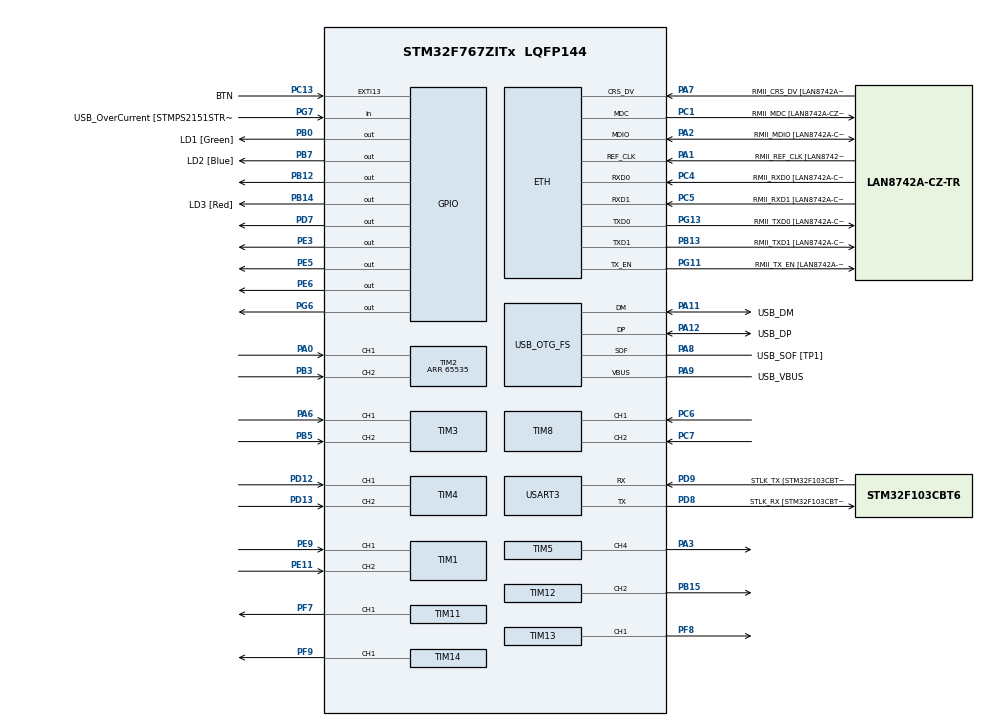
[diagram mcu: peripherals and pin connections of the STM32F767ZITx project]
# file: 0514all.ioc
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ETH.MediaInterface=HAL_ETH_RMII_MODE
ETH.PHY_Name=LAN8742A_PHY_ADDRESS
ETH.PHY_Value=0
ETH.PhyAddress=0
Mcu.Family=STM32F7
Mcu.Name=STM32F767ZITx
Mcu.Package=LQFP144
NVIC.EXTI15_10_IRQn=true\:0\:0\:false\:false\:true\:true\:true\:true
NVIC.PriorityGroup=NVIC_PRIORITYGROUP_4
NVIC.TIM1_BRK_TIM9_IRQn=true\:0\:0\:false\:false\:true\:true\:true\:true
PA0/WKUP.Signal=S_TIM2_CH1_ETR
PA1.GPIO_Label=RMII_REF_CLK [LAN8742A-CZ-TR_REFCLK0]
PA1.Mode=RMII
PA1.Signal=ETH_REF_CLK
PA10.GPIO_Label=USB_ID
PA10.Signal=USB_OTG_FS_ID
PA11.GPIO_Label=USB_DM
PA11.Mode=Device_Only
PA11.Signal=USB_OTG_FS_DM
PA12.GPIO_Label=USB_DP
PA12.Mode=Device_Only
PA12.Signal=USB_OTG_FS_DP
PA13.GPIO_Label=TMS
PA13.Mode=Serial_Wire
PA13.Signal=SYS_JTMS-SWDIO
PA14.GPIO_Label=TCK
PA14.Mode=Serial_Wire
PA14.Signal=SYS_JTCK-SWCLK
PA2.GPIO_Label=RMII_MDIO [LAN8742A-CZ-TR_MDIO]
PA2.Mode=RMII
PA2.Signal=ETH_MDIO
PA3.Signal=S_TIM5_CH4
PA6.Signal=S_TIM3_CH1
PA7.GPIO_Label=RMII_CRS_DV [LAN8742A-CZ-TR_CRS_DV]
PA7.Mode=RMII
PA7.Signal=ETH_CRS_DV
PA8.GPIO_Label=USB_SOF [TP1]
PA8.Mode=Activate_SOF_FS
PA8.Signal=USB_OTG_FS_SOF
PA9.GPIO_Label=USB_VBUS
PA9.Mode=Activate_VBUS
PA9.Signal=USB_OTG_FS_VBUS
PB0.GPIO_Label=LD1 [Green]
PB0.Signal=GPIO_Output
PB12.Signal=GPIO_Output
PB13.GPIO_Label=RMII_TXD1 [LAN8742A-CZ-TR_TXD1]
PB13.Mode=RMII
PB13.Signal=ETH_TXD1
PB14.GPIO_Label=LD3 [Red]
PB14.Signal=GPIO_Output
PB15.Signal=S_TIM12_CH2
PB3.Signal=S_TIM2_CH2
PB5.Signal=S_TIM3_CH2
PB7.GPIO_Label=LD2 [Blue]
PB7.Signal=GPIO_Output
PC1.GPIO_Label=RMII_MDC [LAN8742A-CZ-TR_MDC]
PC1.Mode=RMII
PC1.Signal=ETH_MDC
PC13.GPIO_Label=BTN
PC13.Signal=GPXTI13
PC14/OSC32_IN.Mode=LSE-External-Oscillator
PC14/OSC32_IN.Signal=RCC_OSC32_IN
PC15/OSC32_OUT.Mode=LSE-External-Oscillator
PC15/OSC32_OUT.Signal=RCC_OSC32_OUT
PC4.GPIO_Label=RMII_RXD0 [LAN8742A-CZ-TR_RXD0]
PC4.Mode=RMII
PC4.Signal=ETH_RXD0
PC5.GPIO_Label=RMII_RXD1 [LAN8742A-CZ-TR_RXD1]
PC5.Mode=RMII
PC5.Signal=ETH_RXD1
PC6.Signal=S_TIM8_CH1
PC7.Signal=S_TIM8_CH2
PD12.Signal=S_TIM4_CH1
PD13.Signal=S_TIM4_CH2
PD7.Signal=GPIO_Output
PD8.GPIO_Label=STLK_RX [STM32F103CBT6_PA3]
PD8.Mode=Asynchronous
PD8.Signal=USART3_TX
PD9.GPIO_Label=STLK_TX [STM32F103CBT6_PA2]
PD9.Mode=Asynchronous
PD9.Signal=USART3_RX
PE11.Signal=S_TIM1_CH2
PE3.Signal=GPIO_Output
PE5.Signal=GPIO_Output
PE6.Signal=GPIO_Output
PE9.Signal=S_TIM1_CH1
PF7.Signal=S_TIM11_CH1
PF8.Signal=S_TIM13_CH1
PF9.Signal=S_TIM14_CH1
PG11.GPIO_Label=RMII_TX_EN [LAN8742A-CZ-TR_TXEN]
PG11.Mode=RMII
PG11.Signal=ETH_TX_EN
PG13.GPIO_Label=RMII_TXD0 [LAN8742A-CZ-TR_TXD0]
PG13.Mode=RMII
PG13.Signal=ETH_TXD0
PG6.Signal=GPIO_Output
PG7.GPIO_Label=USB_OverCurrent [STMPS2151STR_FAULT]
PG7.Signal=GPIO_Input
PH0/OSC_IN.GPIO_Label=MCO [STM32F103CBT6_PA8]
PH0/OSC_IN.Mode=HSE-External-Clock-Source
PH0/OSC_IN.Signal=RCC_OSC_IN
PH1/OSC_OUT.Mode=HSE-External-Clock-Source
PH1/OSC_OUT.Signal=RCC_OSC_OUT
ProjectManager.HeapSize=0x200
ProjectManager.StackSize=0x400
ProjectManager.TargetToolchain=STM32CubeIDE
RCC.48MHZClocksFreq_Value=24000000
RCC.AHBFreq_Value=96000000
RCC.APB1CLKDivider=RCC_HCLK_DIV2
RCC.APB1Freq_Value=48000000
RCC.APB1TimFreq_Value=96000000
RCC.APB2Freq_Value=96000000
RCC.APB2TimFreq_Value=96000000
RCC.CortexFreq_Value=96000000
RCC.HCLKFreq_Value=96000000
RCC.HSE_VALUE=8000000
RCC.HSI_VALUE=16000000
RCC.PLLM=4
RCC.PLLMUL=RCC_PLL_MUL9
RCC.PLLN=96
RCC.PLLQ=4
RCC.PRESCALERUSB=RCC_USBCLKSOURCE_PLL_DIV1_5
RCC.SYSCLKFreq_VALUE=96000000
RCC.SYSCLKSource=RCC_SYSCLKSOURCE_PLLCLK
RCC.SYSCLKSourceVirtual=RCC_SYSCLKSOURCE_PLLCLK
RCC.USBFreq_Value=48000000
RCC.VCOOutputFreq_Value=192000000
SH.S_TIM11_CH1.0=TIM11_CH1,PWM Generation1 CH1
SH.S_TIM12_CH2.0=TIM12_CH2,PWM Generation2 CH2
SH.S_TIM13_CH1.0=TIM13_CH1,PWM Generation1 CH1
SH.S_TIM14_CH1.0=TIM14_CH1,PWM Generation1 CH1
SH.S_TIM1_CH1.0=TIM1_CH1,Encoder_Interface
SH.S_TIM1_CH2.0=TIM1_CH2,Encoder_Interface
SH.S_TIM2_CH1_ETR.0=TIM2_CH1,Encoder_Interface
SH.S_TIM2_CH2.0=TIM2_CH2,Encoder_Interface
SH.S_TIM3_CH1.0=TIM3_CH1,Encoder_Interface
SH.S_TIM3_CH2.0=TIM3_CH2,Encoder_Interface
SH.S_TIM4_CH1.0=TIM4_CH1,Encoder_Interface
SH.S_TIM4_CH2.0=TIM4_CH2,Encoder_Interface
SH.S_TIM5_CH4.0=TIM5_CH4,PWM Generation4 CH4
SH.S_TIM8_CH1.0=TIM8_CH1,Encoder_Interface
SH.S_TIM8_CH2.0=TIM8_CH2,Encoder_Interface
TIM1.EncoderMode=TIM_ENCODERMODE_TI12
TIM11.Channel=TIM_CHANNEL_1
TIM11.Period=4200-1
TIM12.Channel-PWM\ Generation2\ CH2=TIM_CHANNEL_2
TIM12.Period=4200-1
TIM13.Channel=TIM_CHANNEL_1
TIM13.Period=4200-1
TIM14.Channel=TIM_CHANNEL_1
TIM14.Period=4200-1
TIM2.EncoderMode=TIM_ENCODERMODE_TI12
TIM2.Period=65535
TIM4.EncoderMode=TIM_ENCODERMODE_TI12
TIM5.Channel-PWM\ Generation4\ CH4=TIM_CHANNEL_4
TIM5.Period=4200-1
TIM8.EncoderMode=TIM_ENCODERMODE_TI12
TIM9.Period=840-1
TIM9.Prescaler=50-1
USART3.VirtualMode-Asynchronous=VM_ASYNC
USB_OTG_FS.VirtualMode=Device_Only
VP_TIM11_VS_ClockSourceINT.Mode=Enable_Timer
VP_TIM13_VS_ClockSourceINT.Mode=Enable_Timer
VP_TIM14_VS_ClockSourceINT.Mode=Enable_Timer
VP_TIM9_VS_ClockSourceINT.Mode=Internal
board=NUCLEO-F767ZI

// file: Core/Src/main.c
/* USER CODE BEGIN Header */
/**
  ******************************************************************************
  * @file           : main.c
  * @brief          : Main program body
  ******************************************************************************
  * @attention
  *
  * Copyright (c) 2023 STMicroelectronics.
  * All rights reserved.
  *
  * This software is licensed under terms that can be found in the LICENSE file
  * in the root directory of this software component.
  * If no LICENSE file comes with this software, it is provided AS-IS.
  *
  ******************************************************************************
  */
/* USER CODE END Header */
#include "main.h"
#include "string.h"

/* USER CODE BEGIN PD */
#define dt_pos 0.05
#define dt_vel 0.005

// ################ etc ######################//
#define pi 3.141592653589793238462643383279502884197169399375105820974944
#define RAD2DEG 57.295779
#define DEG2RAD 0.0174532
#define Ke 0.04
/* USER CODE END PD */

#if defined ( __ICCARM__ ) /*!< IAR Compiler */
#pragma location=0x2007c000
ETH_DMADescTypeDef  DMARxDscrTab[ETH_RX_DESC_CNT]; /* Ethernet Rx DMA Descriptors */
#pragma location=0x2007c0a0
ETH_DMADescTypeDef  DMATxDscrTab[ETH_TX_DESC_CNT]; /* Ethernet Tx DMA Descriptors */

#elif defined ( __CC_ARM )  /* MDK ARM Compiler */

__attribute__((at(0x2007c000))) ETH_DMADescTypeDef  DMARxDscrTab[ETH_RX_DESC_CNT]; /* Ethernet Rx DMA Descriptors */
__attribute__((at(0x2007c0a0))) ETH_DMADescTypeDef  DMATxDscrTab[ETH_TX_DESC_CNT]; /* Ethernet Tx DMA Descriptors */

#elif defined ( __GNUC__ ) /* GNU Compiler */
ETH_DMADescTypeDef DMARxDscrTab[ETH_RX_DESC_CNT] __attribute__((section(".RxDecripSection"))); /* Ethernet Rx DMA Descriptors */
ETH_DMADescTypeDef DMATxDscrTab[ETH_TX_DESC_CNT] __attribute__((section(".TxDecripSection")));   /* Ethernet Tx DMA Descriptors */

#endif

ETH_TxPacketConfig TxConfig;

ETH_HandleTypeDef heth;

TIM_HandleTypeDef htim1;
TIM_HandleTypeDef htim2;
TIM_HandleTypeDef htim3;
TIM_HandleTypeDef htim4;
TIM_HandleTypeDef htim5;
TIM_HandleTypeDef htim8;
TIM_HandleTypeDef htim9;
TIM_HandleTypeDef htim11;
TIM_HandleTypeDef htim12;
TIM_HandleTypeDef htim13;
TIM_HandleTypeDef htim14;

UART_HandleTypeDef huart3;

PCD_HandleTypeDef hpcd_USB_OTG_FS;

/* USER CODE BEGIN PV */

int cnt_control;
int mode = 0;
volatile uint16_t Motor_CCR[5] = {0.0, 0.0, 0.0, 0.0, 0.0};
volatile double g_ref[5] = {0, 0, 0, 0, 0};
volatile double g_Pdes[5] = {0.0, 0.0, 0.0, 0.0, 0.0};
volatile double g_Ppre[5]= {0.0, 0.0, 0.0, 0.0, 0.0};
volatile double g_Pcur[5] = {0.0, 0.0, 0.0, 0.0, 0.0};
volatile double g_Perr[5] = {0.0, 0.0, 0.0, 0.0, 0.0};
volatile double g_Pperr[5] = {0.0, 0.0, 0.0, 0.0, 0.0};
volatile double g_pos_control[5] = {0.0, 0.0, 0.0, 0.0, 0.0};
volatile double Kp_P[5] = {5.0, 6.0, 5.0, 4.0, 5.0};
volatile double Kd_P[5] = {0.8, 0.8, 0.8, 0.3, 0.8};

volatile double Vel_Max[5] = {5, 5, 5, 5, 5};
volatile double Vel_Min[5] = {-5,-5,-5,-5,-5};
volatile double Vel_Ref[5] = {0.0, 0.0, 0.0, 0.0, 0.0};
volatile double Vel_Cur[5] = {0.0, 0.0, 0.0, 0.0, 0.0};
volatile double Vel_Err[5] = {0.0, 0.0, 0.0, 0.0, 0.0};
volatile double Vel_Err_Sum[5] = {0.0, 0.0, 0.0, 0.0, 0.0};
volatile double Vel_Ctrl_Out[5] = {0.0, 0.0, 0.0, 0.0, 0.0};

volatile double Kp_V[5] = {5.0, 3.5, 5.0, 2.0, 3.0};
volatile double Ki_V[5] = {0.2, 3, 2.4, 0.8, 0.2};

volatile uint16_t encoder_cnt[5]= {0.0, 0.0, 0.0, 0.0, 0.0};
volatile uint16_t En_Cnt_Pre[5]= {0.0, 0.0, 0.0, 0.0, 0.0};
volatile int32_t En_Cnt_Err[5]= {0.0, 0.0, 0.0, 0.0, 0.0};
volatile double Angle_Cur[5]= {0.0, 0.0, 0.0, 0.0, 0.0};
volatile double Angle_Curdeg[5]= {0.0, 0.0, 0.0, 0.0, 0.0};
volatile double Angle_Pre[5]= {0.0, 0.0, 0.0, 0.0, 0.0};

/* USER CODE END PV */

void SystemClock_Config(void);
static void MX_GPIO_Init(void);
static void MX_ETH_Init(void);
static void MX_USART3_UART_Init(void);
static void MX_USB_OTG_FS_PCD_Init(void);
static void MX_TIM1_Init(void);
static void MX_TIM2_Init(void);
static void MX_TIM3_Init(void);
static void MX_TIM4_Init(void);
static void MX_TIM8_Init(void);
static void MX_TIM9_Init(void);
static void MX_TIM11_Init(void);
static void MX_TIM12_Init(void);
static void MX_TIM13_Init(void);
static void MX_TIM5_Init(void);
static void MX_TIM14_Init(void);

/* USER CODE BEGIN 0 */
void HAL_TIM_PeriodElapsedCallback(TIM_HandleTypeDef *htim)
{
	if(mode ==1){

		if(htim == &htim9)
		{
	//		cnt++;
	//
			encoder_cnt[0] = TIM1 -> CNT;
			encoder_cnt[1] = TIM2 -> CNT;
			encoder_cnt[2] = TIM3 -> CNT;
			encoder_cnt[3] = TIM4 -> CNT;
			encoder_cnt[4] = TIM8 -> CNT;
	//
	//		TIM5 -> CCR4 = Motor_CCR[0];
	//		HAL_GPIO_WritePin(GPIOD, GPIO_PIN_7, GPIO_PIN_SET);
	//		TIM11 -> CCR1 = Motor_CCR[1];
	//		HAL_GPIO_WritePin(GPIOE, GPIO_PIN_6, GPIO_PIN_SET);
	//		TIM12 -> CCR2 = Motor_CCR[2];
	//		HAL_GPIO_WritePin(GPIOB, GPIO_PIN_12, GPIO_PIN_SET);//cw
	//		TIM13 -> CCR1 = Motor_CCR[3];
	//		HAL_GPIO_WritePin(GPIOE, GPIO_PIN_5, GPIO_PIN_RESET);//ccw
	//		TIM14 -> CCR1 = Motor_CCR[4];
	//		HAL_GPIO_WritePin(GPIOE, GPIO_PIN_3, GPIO_PIN_SET);
			cnt_control++;

				  for(int i = 0; i<5; i++){
			      En_Cnt_Err[i] = (encoder_cnt[i] - En_Cnt_Pre[i]);
				  }
			      // Encoder Exception Handling
				  for(int i = 0; i<5; i++){
			      if (encoder_cnt[i] > 60000 && En_Cnt_Pre[i] < 5000)
			         En_Cnt_Err[i] -= 65535;
			      else if (encoder_cnt[i] < 5000 && En_Cnt_Pre[i] > 60000)
			         En_Cnt_Err[i] += 65535;
				  }
			      // Get Angle
			      Angle_Cur[0] += (En_Cnt_Err[0] / (1024. * 4 * 126.)) * 2 * pi;   // rad
			      Angle_Cur[1] += (En_Cnt_Err[1] / (1024. * 4 * 126.)) * 2 * pi;   // rad
			      Angle_Cur[2] += (En_Cnt_Err[2] / (1024. * 4 * 100.)) * 2 * pi;   // rad
			      Angle_Cur[3] += (En_Cnt_Err[3] / (1024. * 4 * 105.)) * 2 * pi;   // rad
			      Angle_Cur[4] += (En_Cnt_Err[4] / (1024. * 4 * 132.)) * 2 * pi;   // rad

			      for(int i = 0; i<5; i++){
			      Angle_Curdeg[i] = Angle_Cur[i] *RAD2DEG;
			      En_Cnt_Pre[i] = encoder_cnt[i];
				  }
			      // Save Previous Value

			      //////////////////////////////////////////////////////////////////////
			      if(cnt_control % 100 == 0) //
			      {
					 for(int i = 0; i<5; i++){

			         g_Pdes[i] = g_ref[i] * DEG2RAD;

			         g_Pcur[i] = Angle_Cur[i];
			         // D?  ?   ????? ?  ?   previous Error ???
			         g_Pperr[i] = g_Perr[i];

			         // Error ???
			         g_Perr[i] = g_Pdes[i] - g_Pcur[i];

			         // Position Control output = Speed value
			         g_pos_control[i] = Kp_P[i] * g_Perr[i] + Kd_P [i]* ((g_Perr[i] - g_Pperr[i]) / dt_pos);
			         // Saturation
			         if(g_pos_control[i] > 0.75) g_pos_control[i] = 0.75;
			         else if(g_pos_control[i] < -0.75) g_pos_control[i] = -0.75;

					 }
			      }
			      ///////////////////////////////////////////////////////////////////////////

			      if(cnt_control % 10 == 0) //
			      {
			    	 for(int i = 0; i<5; i++){
			    	 Vel_Ref[i] = 	g_pos_control[i];
			         if(Vel_Ref[i] >= 0){
						 // Set Velocity Limit
						 if(Vel_Ref[i] > Vel_Max[i]) Vel_Ref[i] = Vel_Max[i];

						 // Get Velocity
						 Vel_Cur[i] = (Angle_Cur[i] - Angle_Pre[i]) / dt_vel;      // rad/s

						 // Save Previous Value
						 Angle_Pre[i] = Angle_Cur[i];

						 // Get Velocity Err
						 Vel_Err[i] = Vel_Ref[i] - Vel_Cur[i];

						 // Get Velocity Err Sum
						 Vel_Err_Sum[i] += Vel_Err[i];

						 // Get Velocity Control Output
						 Vel_Ctrl_Out[i] = (Kp_V[i] * Vel_Err[i]) + (Ki_V[i] * Vel_Err_Sum[i] * dt_vel);

						 if(Vel_Ctrl_Out[i] < -0.1) Vel_Ctrl_Out[i] = Vel_Cur[i] * 0.5;
						 else if(Vel_Ctrl_Out[i] >= -0.1) Vel_Ctrl_Out[i] = Vel_Ctrl_Out[i]+ 0.75*Vel_Cur[i];
						 // Current saturation & Anti wind-up
						 if(Vel_Ctrl_Out[i] > Vel_Max[i])
						 {
							Vel_Err_Sum[i] -= (Vel_Ctrl_Out[i] - Vel_Max[i]) * (3. / Kp_V[i]);
							Vel_Ctrl_Out[i] = Vel_Max[i];
						 }
						 else if(Vel_Ctrl_Out[i] < Vel_Min[i])
						 {
							Vel_Err_Sum[i] -= (Vel_Ctrl_Out[i] - Vel_Min[i]) * (3. / Kp_V[i]);
							Vel_Ctrl_Out[i] = Vel_Min[i];
						 }
			         }
			         if(Vel_Ref[i] < 0){
						 // Set Velocity Limit
						 if(Vel_Ref[i] < Vel_Min[i]) Vel_Ref[i] = Vel_Min[i];

						 // Get Velocity
						 Vel_Cur[i] = (Angle_Cur[i] - Angle_Pre[i]) / dt_vel;      // rad/s

						 // Save Previous Value
						 Angle_Pre[i] = Angle_Cur[i];

						 // Get Velocity Err
						 Vel_Err[i] = Vel_Ref[i] - Vel_Cur[i];

						 // Get Velocity Err Sum
						 Vel_Err_Sum[i] += Vel_Err[i];

						 // Get Velocity Control Output
						 Vel_Ctrl_Out[i] = (Kp_V[i] * Vel_Err[i]) + (Ki_V[i] * Vel_Err_Sum[i] * dt_vel);

						 if(Vel_Ctrl_Out[i] > +0.1) Vel_Ctrl_Out[i] = Vel_Cur[i] * 0.5;
						 else if(Vel_Ctrl_Out[i] <= +0.1) Vel_Ctrl_Out[i] = Vel_Ctrl_Out[i] + 0.75*Vel_Cur[i];
						 // Current saturation & Anti wind-up
						 if(Vel_Ctrl_Out[i] < Vel_Min[i])
						 {
							Vel_Err_Sum[i] -= (Vel_Ctrl_Out[i] - Vel_Min[i]) * (3. / Kp_V[i]);
							Vel_Ctrl_Out[i] = Vel_Min[i];
						 }
			         }
			    	 }

			      }
			      if(cnt_control % 2 == 0){
			    	 for(int i = 0; i<5; i++){
			 			Make_PWM(Vel_Ctrl_Out[0], Vel_Ctrl_Out[1], Vel_Ctrl_Out[2], Vel_Ctrl_Out[3], Vel_Ctrl_Out[4]);

					  }
			      }
		}
	}
}

void Make_PWM(double input_0, double input_1, double input_2, double input_3, double input_4)
{
	// Generate Motor PWM 0
    if(input_0 < 0)
    {
       Motor_CCR[0] = (double)((-Vel_Ctrl_Out[0] / Vel_Max[0]) * 4119);
       HAL_GPIO_WritePin(GPIOD, GPIO_PIN_7, GPIO_PIN_RESET);
       TIM5-> CCR4 = Motor_CCR[0];
    }
    else
    {
       Motor_CCR[0] = (double)((Vel_Ctrl_Out[0] / Vel_Max[0]) * 4119);
       HAL_GPIO_WritePin(GPIOD, GPIO_PIN_7, GPIO_PIN_SET);
       TIM5 -> CCR4 = Motor_CCR[0];
    }

	// Generate Motor PWM 1
    if(input_1 < 0)
    {
       Motor_CCR[1] = (double)((-Vel_Ctrl_Out[1] / Vel_Max[1]) * 4119);
       HAL_GPIO_WritePin(GPIOE, GPIO_PIN_6, GPIO_PIN_RESET);
       TIM11-> CCR1 = Motor_CCR[1];
    }
    else
    {
       Motor_CCR[1] = (double)((Vel_Ctrl_Out[1] / Vel_Max[1]) * 4119);
       HAL_GPIO_WritePin(GPIOE, GPIO_PIN_6, GPIO_PIN_SET);
       TIM11 -> CCR1 = Motor_CCR[1];
    }

	// Generate Motor PWM 2
    if(input_2 < 0)
    {
       Motor_CCR[2] = (double)((-Vel_Ctrl_Out[2] / Vel_Max[2]) * 4119);
       HAL_GPIO_WritePin(GPIOB, GPIO_PIN_12, GPIO_PIN_RESET);
       TIM12-> CCR2 = Motor_CCR[2];
    }
    else
    {
       Motor_CCR[2] = (double)((Vel_Ctrl_Out[2] / Vel_Max[2]) * 4119);
       HAL_GPIO_WritePin(GPIOB, GPIO_PIN_12, GPIO_PIN_SET);
       TIM12 -> CCR2 = Motor_CCR[2];
    }

	// Generate Motor PWM 3
	if(input_3 < 0)
	{
	   Motor_CCR[3] = (double)((-Vel_Ctrl_Out[3] / Vel_Max[3]) * 4119);
	   HAL_GPIO_WritePin(GPIOE, GPIO_PIN_5, GPIO_PIN_RESET);
	   TIM13-> CCR1 = Motor_CCR[3];
	}
	else
	{
	   Motor_CCR[3] = (double)((Vel_Ctrl_Out[3] / Vel_Max[3]) * 4119);
	   HAL_GPIO_WritePin(GPIOE, GPIO_PIN_5, GPIO_PIN_SET);
	   TIM13 -> CCR1 = Motor_CCR[3];
	}
	// Generate Motor PWM 4
    if(input_4 < 0)
    {
       Motor_CCR[4] = (double)((-Vel_Ctrl_Out[4] / Vel_Max[4]) * 4119);
       HAL_GPIO_WritePin(GPIOD, GPIO_PIN_7, GPIO_PIN_RESET);
       TIM14-> CCR1 = Motor_CCR[4];
    }
    else
    {
       Motor_CCR[4] = (double)((Vel_Ctrl_Out[4] / Vel_Max[4]) * 4119);
       HAL_GPIO_WritePin(GPIOD, GPIO_PIN_7, GPIO_PIN_SET);
       TIM14 -> CCR1 = Motor_CCR[4];
    }

}

/* USER CODE END 0 */

int main(void)
{

  /* MCU Configuration--------------------------------------------------------*/

  /* Reset of all peripherals, Initializes the Flash interface and the Systick. */
  HAL_Init();

  /* Configure the system clock */
  SystemClock_Config();

  /* Initialize all configured peripherals */
  MX_GPIO_Init();
  MX_ETH_Init();
  MX_USART3_UART_Init();
  MX_USB_OTG_FS_PCD_Init();
  MX_TIM1_Init();
  MX_TIM2_Init();
  MX_TIM3_Init();
  MX_TIM4_Init();
  MX_TIM8_Init();
  MX_TIM9_Init();
  MX_TIM11_Init();
  MX_TIM12_Init();
  MX_TIM13_Init();
  MX_TIM5_Init();
  MX_TIM14_Init();
  /* USER CODE BEGIN 2 */
  HAL_TIM_Base_Start_IT(&htim9);

  HAL_TIM_PWM_Start(&htim5, TIM_CHANNEL_4);
  HAL_TIMEx_PWMN_Start(&htim5, TIM_CHANNEL_4);

  HAL_TIM_PWM_Start(&htim11, TIM_CHANNEL_1);
  HAL_TIMEx_PWMN_Start(&htim11, TIM_CHANNEL_1);

  HAL_TIM_PWM_Start(&htim12, TIM_CHANNEL_2);
  HAL_TIMEx_PWMN_Start(&htim12, TIM_CHANNEL_2);

  HAL_TIM_PWM_Start(&htim13, TIM_CHANNEL_1);
  HAL_TIMEx_PWMN_Start(&htim13, TIM_CHANNEL_1);

  HAL_TIM_PWM_Start(&htim14, TIM_CHANNEL_1);
  HAL_TIMEx_PWMN_Start(&htim14, TIM_CHANNEL_1);

  HAL_TIM_Encoder_Start(&htim1, TIM_CHANNEL_ALL);
  HAL_TIM_Encoder_Start(&htim2, TIM_CHANNEL_ALL);
  HAL_TIM_Encoder_Start(&htim3, TIM_CHANNEL_ALL);
  HAL_TIM_Encoder_Start(&htim4, TIM_CHANNEL_ALL);
  HAL_TIM_Encoder_Start(&htim8, TIM_CHANNEL_ALL);

  /* USER CODE END 2 */

  /* Infinite loop */
  while (1)
  {

  }
}
void HAL_GPIO_EXTI_Callback(uint16_t GPIO_Pin)
{
	if(GPIO_Pin == BTN_Pin)
	{
		HAL_GPIO_TogglePin(LD1_GPIO_Port, LD1_Pin);  // LED 모드 변경
		if(mode == 0) mode = 1;
		for(int i =0; i < 5; i++) g_ref[i] = 90 +  g_ref[i];
	}
}
void SystemClock_Config(void)
{
  RCC_OscInitTypeDef RCC_OscInitStruct = {0};
  RCC_ClkInitTypeDef RCC_ClkInitStruct = {0};

  /** Configure LSE Drive Capability
  */
  HAL_PWR_EnableBkUpAccess();

  /** Configure the main internal regulator output voltage
  */
  __HAL_RCC_PWR_CLK_ENABLE();
  __HAL_PWR_VOLTAGESCALING_CONFIG(PWR_REGULATOR_VOLTAGE_SCALE3);

  /** Initializes the RCC Oscillators according to the specified parameters
  * in the RCC_OscInitTypeDef structure.
  */
  RCC_OscInitStruct.OscillatorType = RCC_OSCILLATORTYPE_HSE;
  RCC_OscInitStruct.HSEState = RCC_HSE_BYPASS;
  RCC_OscInitStruct.PLL.PLLState = RCC_PLL_ON;
  RCC_OscInitStruct.PLL.PLLSource = RCC_PLLSOURCE_HSE;
  RCC_OscInitStruct.PLL.PLLM = 4;
  RCC_OscInitStruct.PLL.PLLN = 168;
  RCC_OscInitStruct.PLL.PLLP = RCC_PLLP_DIV2;
  RCC_OscInitStruct.PLL.PLLQ = 7;
  RCC_OscInitStruct.PLL.PLLR = 2;
  if (HAL_RCC_OscConfig(&RCC_OscInitStruct) != HAL_OK)
  {
    Error_Handler();
  }

  /** Initializes the CPU, AHB and APB buses clocks
  */
  RCC_ClkInitStruct.ClockType = RCC_CLOCKTYPE_HCLK|RCC_CLOCKTYPE_SYSCLK
                              |RCC_CLOCKTYPE_PCLK1|RCC_CLOCKTYPE_PCLK2;
  RCC_ClkInitStruct.SYSCLKSource = RCC_SYSCLKSOURCE_PLLCLK;
  RCC_ClkInitStruct.AHBCLKDivider = RCC_SYSCLK_DIV2;
  RCC_ClkInitStruct.APB1CLKDivider = RCC_HCLK_DIV2;
  RCC_ClkInitStruct.APB2CLKDivider = RCC_HCLK_DIV1;

  if (HAL_RCC_ClockConfig(&RCC_ClkInitStruct, FLASH_LATENCY_2) != HAL_OK)
  {
    Error_Handler();
  }
}

static void MX_ETH_Init(void)
{

   static uint8_t MACAddr[6];

  heth.Instance = ETH;
  MACAddr[0] = 0x00;
  MACAddr[1] = 0x80;
  MACAddr[2] = 0xE1;
  MACAddr[3] = 0x00;
  MACAddr[4] = 0x00;
  MACAddr[5] = 0x00;
  heth.Init.MACAddr = &MACAddr[0];
  heth.Init.MediaInterface = HAL_ETH_RMII_MODE;
  heth.Init.TxDesc = DMATxDscrTab;
  heth.Init.RxDesc = DMARxDscrTab;
  heth.Init.RxBuffLen = 1524;

  if (HAL_ETH_Init(&heth) != HAL_OK)
  {
    Error_Handler();
  }

  memset(&TxConfig, 0 , sizeof(ETH_TxPacketConfig));
  TxConfig.Attributes = ETH_TX_PACKETS_FEATURES_CSUM | ETH_TX_PACKETS_FEATURES_CRCPAD;
  TxConfig.ChecksumCtrl = ETH_CHECKSUM_IPHDR_PAYLOAD_INSERT_PHDR_CALC;
  TxConfig.CRCPadCtrl = ETH_CRC_PAD_INSERT;

}

static void MX_TIM1_Init(void)
{

  TIM_Encoder_InitTypeDef sConfig = {0};
  TIM_MasterConfigTypeDef sMasterConfig = {0};

  htim1.Instance = TIM1;
  htim1.Init.Prescaler = 0;
  htim1.Init.CounterMode = TIM_COUNTERMODE_UP;
  htim1.Init.Period = 65535;
  htim1.Init.ClockDivision = TIM_CLOCKDIVISION_DIV1;
  htim1.Init.RepetitionCounter = 0;
  htim1.Init.AutoReloadPreload = TIM_AUTORELOAD_PRELOAD_DISABLE;
  sConfig.EncoderMode = TIM_ENCODERMODE_TI12;
  sConfig.IC1Polarity = TIM_ICPOLARITY_RISING;
  sConfig.IC1Selection = TIM_ICSELECTION_DIRECTTI;
  sConfig.IC1Prescaler = TIM_ICPSC_DIV1;
  sConfig.IC1Filter = 0;
  sConfig.IC2Polarity = TIM_ICPOLARITY_RISING;
  sConfig.IC2Selection = TIM_ICSELECTION_DIRECTTI;
  sConfig.IC2Prescaler = TIM_ICPSC_DIV1;
  sConfig.IC2Filter = 0;
  if (HAL_TIM_Encoder_Init(&htim1, &sConfig) != HAL_OK)
  {
    Error_Handler();
  }
  sMasterConfig.MasterOutputTrigger = TIM_TRGO_RESET;
  sMasterConfig.MasterOutputTrigger2 = TIM_TRGO2_RESET;
  sMasterConfig.MasterSlaveMode = TIM_MASTERSLAVEMODE_DISABLE;
  if (HAL_TIMEx_MasterConfigSynchronization(&htim1, &sMasterConfig) != HAL_OK)
  {
    Error_Handler();
  }

}

static void MX_TIM2_Init(void)
{

  TIM_Encoder_InitTypeDef sConfig = {0};
  TIM_MasterConfigTypeDef sMasterConfig = {0};

  htim2.Instance = TIM2;
  htim2.Init.Prescaler = 0;
  htim2.Init.CounterMode = TIM_COUNTERMODE_UP;
  htim2.Init.Period = 65535;
  htim2.Init.ClockDivision = TIM_CLOCKDIVISION_DIV1;
  htim2.Init.AutoReloadPreload = TIM_AUTORELOAD_PRELOAD_DISABLE;
  sConfig.EncoderMode = TIM_ENCODERMODE_TI12;
  sConfig.IC1Polarity = TIM_ICPOLARITY_RISING;
  sConfig.IC1Selection = TIM_ICSELECTION_DIRECTTI;
  sConfig.IC1Prescaler = TIM_ICPSC_DIV1;
  sConfig.IC1Filter = 0;
  sConfig.IC2Polarity = TIM_ICPOLARITY_RISING;
  sConfig.IC2Selection = TIM_ICSELECTION_DIRECTTI;
  sConfig.IC2Prescaler = TIM_ICPSC_DIV1;
  sConfig.IC2Filter = 0;
  if (HAL_TIM_Encoder_Init(&htim2, &sConfig) != HAL_OK)
  {
    Error_Handler();
  }
  sMasterConfig.MasterOutputTrigger = TIM_TRGO_RESET;
  sMasterConfig.MasterSlaveMode = TIM_MASTERSLAVEMODE_DISABLE;
  if (HAL_TIMEx_MasterConfigSynchronization(&htim2, &sMasterConfig) != HAL_OK)
  {
    Error_Handler();
  }

}

static void MX_TIM3_Init(void)
{

  TIM_Encoder_InitTypeDef sConfig = {0};
  TIM_MasterConfigTypeDef sMasterConfig = {0};

  htim3.Instance = TIM3;
  htim3.Init.Prescaler = 0;
  htim3.Init.CounterMode = TIM_COUNTERMODE_UP;
  htim3.Init.Period = 65535;
  htim3.Init.ClockDivision = TIM_CLOCKDIVISION_DIV1;
  htim3.Init.AutoReloadPreload = TIM_AUTORELOAD_PRELOAD_DISABLE;
  sConfig.EncoderMode = TIM_ENCODERMODE_TI12;
  sConfig.IC1Polarity = TIM_ICPOLARITY_RISING;
  sConfig.IC1Selection = TIM_ICSELECTION_DIRECTTI;
  sConfig.IC1Prescaler = TIM_ICPSC_DIV1;
  sConfig.IC1Filter = 0;
  sConfig.IC2Polarity = TIM_ICPOLARITY_RISING;
  sConfig.IC2Selection = TIM_ICSELECTION_DIRECTTI;
  sConfig.IC2Prescaler = TIM_ICPSC_DIV1;
  sConfig.IC2Filter = 0;
  if (HAL_TIM_Encoder_Init(&htim3, &sConfig) != HAL_OK)
  {
    Error_Handler();
  }
  sMasterConfig.MasterOutputTrigger = TIM_TRGO_RESET;
  sMasterConfig.MasterSlaveMode = TIM_MASTERSLAVEMODE_DISABLE;
  if (HAL_TIMEx_MasterConfigSynchronization(&htim3, &sMasterConfig) != HAL_OK)
  {
    Error_Handler();
  }

}

static void MX_TIM4_Init(void)
{

  TIM_Encoder_InitTypeDef sConfig = {0};
  TIM_MasterConfigTypeDef sMasterConfig = {0};

  htim4.Instance = TIM4;
  htim4.Init.Prescaler = 0;
  htim4.Init.CounterMode = TIM_COUNTERMODE_UP;
  htim4.Init.Period = 65535;
  htim4.Init.ClockDivision = TIM_CLOCKDIVISION_DIV1;
  htim4.Init.AutoReloadPreload = TIM_AUTORELOAD_PRELOAD_DISABLE;
  sConfig.EncoderMode = TIM_ENCODERMODE_TI12;
  sConfig.IC1Polarity = TIM_ICPOLARITY_RISING;
  sConfig.IC1Selection = TIM_ICSELECTION_DIRECTTI;
  sConfig.IC1Prescaler = TIM_ICPSC_DIV1;
  sConfig.IC1Filter = 0;
  sConfig.IC2Polarity = TIM_ICPOLARITY_RISING;
  sConfig.IC2Selection = TIM_ICSELECTION_DIRECTTI;
  sConfig.IC2Prescaler = TIM_ICPSC_DIV1;
  sConfig.IC2Filter = 0;
  if (HAL_TIM_Encoder_Init(&htim4, &sConfig) != HAL_OK)
  {
    Error_Handler();
  }
  sMasterConfig.MasterOutputTrigger = TIM_TRGO_RESET;
  sMasterConfig.MasterSlaveMode = TIM_MASTERSLAVEMODE_DISABLE;
  if (HAL_TIMEx_MasterConfigSynchronization(&htim4, &sMasterConfig) != HAL_OK)
  {
    Error_Handler();
  }

}

static void MX_TIM5_Init(void)
{

  TIM_MasterConfigTypeDef sMasterConfig = {0};
  TIM_OC_InitTypeDef sConfigOC = {0};

  htim5.Instance = TIM5;
  htim5.Init.Prescaler = 0;
  htim5.Init.CounterMode = TIM_COUNTERMODE_UP;
  htim5.Init.Period = 4200-1;
  htim5.Init.ClockDivision = TIM_CLOCKDIVISION_DIV1;
  htim5.Init.AutoReloadPreload = TIM_AUTORELOAD_PRELOAD_DISABLE;
  if (HAL_TIM_PWM_Init(&htim5) != HAL_OK)
  {
    Error_Handler();
  }
  sMasterConfig.MasterOutputTrigger = TIM_TRGO_RESET;
  sMasterConfig.MasterSlaveMode = TIM_MASTERSLAVEMODE_DISABLE;
  if (HAL_TIMEx_MasterConfigSynchronization(&htim5, &sMasterConfig) != HAL_OK)
  {
    Error_Handler();
  }
  sConfigOC.OCMode = TIM_OCMODE_PWM1;
  sConfigOC.Pulse = 0;
  sConfigOC.OCPolarity = TIM_OCPOLARITY_HIGH;
  sConfigOC.OCFastMode = TIM_OCFAST_DISABLE;
  if (HAL_TIM_PWM_ConfigChannel(&htim5, &sConfigOC, TIM_CHANNEL_4) != HAL_OK)
  {
    Error_Handler();
  }
  HAL_TIM_MspPostInit(&htim5);

}

static void MX_TIM8_Init(void)
{

  TIM_Encoder_InitTypeDef sConfig = {0};
  TIM_MasterConfigTypeDef sMasterConfig = {0};

  htim8.Instance = TIM8;
  htim8.Init.Prescaler = 0;
  htim8.Init.CounterMode = TIM_COUNTERMODE_UP;
  htim8.Init.Period = 65535;
  htim8.Init.ClockDivision = TIM_CLOCKDIVISION_DIV1;
  htim8.Init.RepetitionCounter = 0;
  htim8.Init.AutoReloadPreload = TIM_AUTORELOAD_PRELOAD_DISABLE;
  sConfig.EncoderMode = TIM_ENCODERMODE_TI12;
  sConfig.IC1Polarity = TIM_ICPOLARITY_RISING;
  sConfig.IC1Selection = TIM_ICSELECTION_DIRECTTI;
  sConfig.IC1Prescaler = TIM_ICPSC_DIV1;
  sConfig.IC1Filter = 0;
  sConfig.IC2Polarity = TIM_ICPOLARITY_RISING;
  sConfig.IC2Selection = TIM_ICSELECTION_DIRECTTI;
  sConfig.IC2Prescaler = TIM_ICPSC_DIV1;
  sConfig.IC2Filter = 0;
  if (HAL_TIM_Encoder_Init(&htim8, &sConfig) != HAL_OK)
  {
    Error_Handler();
  }
  sMasterConfig.MasterOutputTrigger = TIM_TRGO_RESET;
  sMasterConfig.MasterOutputTrigger2 = TIM_TRGO2_RESET;
  sMasterConfig.MasterSlaveMode = TIM_MASTERSLAVEMODE_DISABLE;
  if (HAL_TIMEx_MasterConfigSynchronization(&htim8, &sMasterConfig) != HAL_OK)
  {
    Error_Handler();
  }

}

static void MX_TIM9_Init(void)
{

  TIM_ClockConfigTypeDef sClockSourceConfig = {0};

  htim9.Instance = TIM9;
  htim9.Init.Prescaler = 840-1;
  htim9.Init.CounterMode = TIM_COUNTERMODE_UP;
  htim9.Init.Period = 50-1;
  htim9.Init.ClockDivision = TIM_CLOCKDIVISION_DIV1;
  htim9.Init.AutoReloadPreload = TIM_AUTORELOAD_PRELOAD_DISABLE;
  if (HAL_TIM_Base_Init(&htim9) != HAL_OK)
  {
    Error_Handler();
  }
  sClockSourceConfig.ClockSource = TIM_CLOCKSOURCE_INTERNAL;
  if (HAL_TIM_ConfigClockSource(&htim9, &sClockSourceConfig) != HAL_OK)
  {
    Error_Handler();
  }

}

static void MX_TIM11_Init(void)
{

  TIM_OC_InitTypeDef sConfigOC = {0};

  htim11.Instance = TIM11;
  htim11.Init.Prescaler = 0;
  htim11.Init.CounterMode = TIM_COUNTERMODE_UP;
  htim11.Init.Period = 4200-1;
  htim11.Init.ClockDivision = TIM_CLOCKDIVISION_DIV1;
  htim11.Init.AutoReloadPreload = TIM_AUTORELOAD_PRELOAD_DISABLE;
  if (HAL_TIM_Base_Init(&htim11) != HAL_OK)
  {
    Error_Handler();
  }
  if (HAL_TIM_PWM_Init(&htim11) != HAL_OK)
  {
    Error_Handler();
  }
  sConfigOC.OCMode = TIM_OCMODE_PWM1;
  sConfigOC.Pulse = 0;
  sConfigOC.OCPolarity = TIM_OCPOLARITY_HIGH;
  sConfigOC.OCFastMode = TIM_OCFAST_DISABLE;
  if (HAL_TIM_PWM_ConfigChannel(&htim11, &sConfigOC, TIM_CHANNEL_1) != HAL_OK)
  {
    Error_Handler();
  }
  HAL_TIM_MspPostInit(&htim11);

}

static void MX_TIM12_Init(void)
{

  TIM_OC_InitTypeDef sConfigOC = {0};

  htim12.Instance = TIM12;
  htim12.Init.Prescaler = 0;
  htim12.Init.CounterMode = TIM_COUNTERMODE_UP;
  htim12.Init.Period = 4200-1;
  htim12.Init.ClockDivision = TIM_CLOCKDIVISION_DIV1;
  htim12.Init.AutoReloadPreload = TIM_AUTORELOAD_PRELOAD_DISABLE;
  if (HAL_TIM_PWM_Init(&htim12) != HAL_OK)
  {
    Error_Handler();
  }
  sConfigOC.OCMode = TIM_OCMODE_PWM1;
  sConfigOC.Pulse = 0;
  sConfigOC.OCPolarity = TIM_OCPOLARITY_HIGH;
  sConfigOC.OCFastMode = TIM_OCFAST_DISABLE;
  if (HAL_TIM_PWM_ConfigChannel(&htim12, &sConfigOC, TIM_CHANNEL_2) != HAL_OK)
  {
    Error_Handler();
  }
  HAL_TIM_MspPostInit(&htim12);

}

static void MX_TIM13_Init(void)
{

  TIM_OC_InitTypeDef sConfigOC = {0};

  htim13.Instance = TIM13;
  htim13.Init.Prescaler = 0;
  htim13.Init.CounterMode = TIM_COUNTERMODE_UP;
  htim13.Init.Period = 4200-1;
  htim13.Init.ClockDivision = TIM_CLOCKDIVISION_DIV1;
  htim13.Init.AutoReloadPreload = TIM_AUTORELOAD_PRELOAD_DISABLE;
  if (HAL_TIM_Base_Init(&htim13) != HAL_OK)
  {
    Error_Handler();
  }
  if (HAL_TIM_PWM_Init(&htim13) != HAL_OK)
  {
    Error_Handler();
  }
  sConfigOC.OCMode = TIM_OCMODE_PWM1;
  sConfigOC.Pulse = 0;
  sConfigOC.OCPolarity = TIM_OCPOLARITY_HIGH;
  sConfigOC.OCFastMode = TIM_OCFAST_DISABLE;
  if (HAL_TIM_PWM_ConfigChannel(&htim13, &sConfigOC, TIM_CHANNEL_1) != HAL_OK)
  {
    Error_Handler();
  }
  HAL_TIM_MspPostInit(&htim13);

}

static void MX_TIM14_Init(void)
{

  TIM_OC_InitTypeDef sConfigOC = {0};

  htim14.Instance = TIM14;
  htim14.Init.Prescaler = 0;
  htim14.Init.CounterMode = TIM_COUNTERMODE_UP;
  htim14.Init.Period = 4200-1;
  htim14.Init.ClockDivision = TIM_CLOCKDIVISION_DIV1;
  htim14.Init.AutoReloadPreload = TIM_AUTORELOAD_PRELOAD_DISABLE;
  if (HAL_TIM_Base_Init(&htim14) != HAL_OK)
  {
    Error_Handler();
  }
  if (HAL_TIM_PWM_Init(&htim14) != HAL_OK)
  {
    Error_Handler();
  }
  sConfigOC.OCMode = TIM_OCMODE_PWM1;
  sConfigOC.Pulse = 0;
  sConfigOC.OCPolarity = TIM_OCPOLARITY_HIGH;
  sConfigOC.OCFastMode = TIM_OCFAST_DISABLE;
  if (HAL_TIM_PWM_ConfigChannel(&htim14, &sConfigOC, TIM_CHANNEL_1) != HAL_OK)
  {
    Error_Handler();
  }
  HAL_TIM_MspPostInit(&htim14);

}

static void MX_USART3_UART_Init(void)
{

  huart3.Instance = USART3;
  huart3.Init.BaudRate = 115200;
  huart3.Init.WordLength = UART_WORDLENGTH_8B;
  huart3.Init.StopBits = UART_STOPBITS_1;
  huart3.Init.Parity = UART_PARITY_NONE;
  huart3.Init.Mode = UART_MODE_TX_RX;
  huart3.Init.HwFlowCtl = UART_HWCONTROL_NONE;
  huart3.Init.OverSampling = UART_OVERSAMPLING_16;
  huart3.Init.OneBitSampling = UART_ONE_BIT_SAMPLE_DISABLE;
  huart3.AdvancedInit.AdvFeatureInit = UART_ADVFEATURE_NO_INIT;
  if (HAL_UART_Init(&huart3) != HAL_OK)
  {
    Error_Handler();
  }

}

static void MX_USB_OTG_FS_PCD_Init(void)
{

  hpcd_USB_OTG_FS.Instance = USB_OTG_FS;
  hpcd_USB_OTG_FS.Init.dev_endpoints = 6;
  hpcd_USB_OTG_FS.Init.speed = PCD_SPEED_FULL;
  hpcd_USB_OTG_FS.Init.dma_enable = DISABLE;
  hpcd_USB_OTG_FS.Init.phy_itface = PCD_PHY_EMBEDDED;
  hpcd_USB_OTG_FS.Init.Sof_enable = ENABLE;
  hpcd_USB_OTG_FS.Init.low_power_enable = DISABLE;
  hpcd_USB_OTG_FS.Init.lpm_enable = DISABLE;
  hpcd_USB_OTG_FS.Init.vbus_sensing_enable = ENABLE;
  hpcd_USB_OTG_FS.Init.use_dedicated_ep1 = DISABLE;
  if (HAL_PCD_Init(&hpcd_USB_OTG_FS) != HAL_OK)
  {
    Error_Handler();
  }

}

static void MX_GPIO_Init(void)
{
  GPIO_InitTypeDef GPIO_InitStruct = {0};

  /* GPIO Ports Clock Enable */
  __HAL_RCC_GPIOE_CLK_ENABLE();
  __HAL_RCC_GPIOC_CLK_ENABLE();
  __HAL_RCC_GPIOF_CLK_ENABLE();
  __HAL_RCC_GPIOH_CLK_ENABLE();
  __HAL_RCC_GPIOA_CLK_ENABLE();
  __HAL_RCC_GPIOB_CLK_ENABLE();
  __HAL_RCC_GPIOD_CLK_ENABLE();
  __HAL_RCC_GPIOG_CLK_ENABLE();

  /*Configure GPIO pin Output Level */
  HAL_GPIO_WritePin(GPIOE, GPIO_PIN_3|GPIO_PIN_5|GPIO_PIN_6, GPIO_PIN_RESET);

  /*Configure GPIO pin Output Level */
  HAL_GPIO_WritePin(GPIOB, LD1_Pin|GPIO_PIN_12|LD2_Pin, GPIO_PIN_RESET);

  /*Configure GPIO pin Output Level */
  HAL_GPIO_WritePin(GPIOG, GPIO_PIN_6, GPIO_PIN_RESET);

  /*Configure GPIO pin Output Level */
  HAL_GPIO_WritePin(GPIOD, GPIO_PIN_7, GPIO_PIN_RESET);

  /*Configure GPIO pins : PE3 PE5 PE6 */
  GPIO_InitStruct.Pin = GPIO_PIN_3|GPIO_PIN_5|GPIO_PIN_6;
  GPIO_InitStruct.Mode = GPIO_MODE_OUTPUT_PP;
  GPIO_InitStruct.Pull = GPIO_NOPULL;
  GPIO_InitStruct.Speed = GPIO_SPEED_FREQ_LOW;
  HAL_GPIO_Init(GPIOE, &GPIO_InitStruct);

  /*Configure GPIO pin : BTN_Pin */
  GPIO_InitStruct.Pin = BTN_Pin;
  GPIO_InitStruct.Mode = GPIO_MODE_IT_RISING;
  GPIO_InitStruct.Pull = GPIO_NOPULL;
  HAL_GPIO_Init(BTN_GPIO_Port, &GPIO_InitStruct);

  /*Configure GPIO pins : LD1_Pin PB12 LD2_Pin */
  GPIO_InitStruct.Pin = LD1_Pin|GPIO_PIN_12|LD2_Pin;
  GPIO_InitStruct.Mode = GPIO_MODE_OUTPUT_PP;
  GPIO_InitStruct.Pull = GPIO_NOPULL;
  GPIO_InitStruct.Speed = GPIO_SPEED_FREQ_LOW;
  HAL_GPIO_Init(GPIOB, &GPIO_InitStruct);

  /*Configure GPIO pin : PG6 */
  GPIO_InitStruct.Pin = GPIO_PIN_6;
  GPIO_InitStruct.Mode = GPIO_MODE_OUTPUT_PP;
  GPIO_InitStruct.Pull = GPIO_NOPULL;
  GPIO_InitStruct.Speed = GPIO_SPEED_FREQ_LOW;
  HAL_GPIO_Init(GPIOG, &GPIO_InitStruct);

  /*Configure GPIO pin : USB_OverCurrent_Pin */
  GPIO_InitStruct.Pin = USB_OverCurrent_Pin;
  GPIO_InitStruct.Mode = GPIO_MODE_INPUT;
  GPIO_InitStruct.Pull = GPIO_NOPULL;
  HAL_GPIO_Init(USB_OverCurrent_GPIO_Port, &GPIO_InitStruct);

  /*Configure GPIO pin : PD7 */
  GPIO_InitStruct.Pin = GPIO_PIN_7;
  GPIO_InitStruct.Mode = GPIO_MODE_OUTPUT_PP;
  GPIO_InitStruct.Pull = GPIO_NOPULL;
  GPIO_InitStruct.Speed = GPIO_SPEED_FREQ_LOW;
  HAL_GPIO_Init(GPIOD, &GPIO_InitStruct);

  /* EXTI interrupt init*/
  HAL_NVIC_SetPriority(EXTI15_10_IRQn, 0, 0);
  HAL_NVIC_EnableIRQ(EXTI15_10_IRQn);

}

void Error_Handler(void)
{
  __disable_irq();
  while (1)
  {
  }
}
